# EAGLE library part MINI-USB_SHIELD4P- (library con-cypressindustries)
MINI USB 4 Pol. Source: www.cypressindustries.com

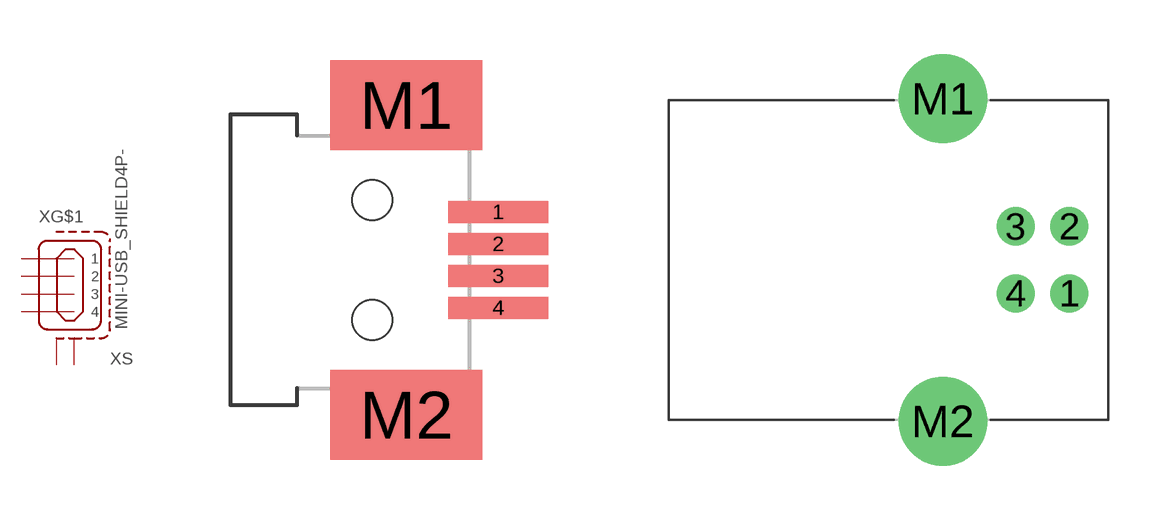
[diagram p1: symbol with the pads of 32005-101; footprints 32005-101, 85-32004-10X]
Designator prefix X; gates G$1=MINI-USB-4P- S=SHIELD_2

## MINI-USB_SHIELD4P-32005-101 (OC_FARNELL: unknown; OC_NEWARK: unknown)  [32005-101]
1  G$1:1  pas
2  G$1:2  pas
3  G$1:3  pas
4  G$1:4  pas
M1  S:S1  pas
M2  S:S2  pas

## MINI-USB_SHIELD4P-85-32004-10X (OC_FARNELL: unknown; OC_NEWARK: unknown)  [85-32004-10X]
Pads as for 32005-101

## MINI-USB_SHIELD4P-85-32004-30X-1 (OC_FARNELL: unknown; OC_NEWARK: unknown)  [85-32004-30X-1]
Pads as for 32005-101

## MINI-USB_SHIELD4P-85-32006-001-1 (OC_FARNELL: unknown; OC_NEWARK: unknown)  [85-32006-001-1]
Pads as for 32005-101

## MINI-USB_SHIELD4P-85-32006-201-1 (OC_FARNELL: unknown; OC_NEWARK: unknown)  [85-32006-201-1]
Pads as for 32005-101

## MINI-USB_SHIELD4P-85-32006-601-1 (OC_FARNELL: unknown; OC_NEWARK: unknown)  [85-32006-601-1]
Pads as for 32005-101

## MINI-USB_SHIELD4P-32005-00X (OC_FARNELL: unknown; OC_NEWARK: unknown)  [32005-00X]
Pads as for 32005-101

## MINI-USB_SHIELD4P-85-32004-00X (OC_FARNELL: unknown; OC_NEWARK: unknown)  [85-32004-00X]
Pads as for 32005-101

## Footprint 32005-101 (pad centres in mm)
MINI USB 4P R/A SMT Two Salient Point Source: http://www.cypressindustries.com/pdf/32005-101.pdf
smd 2.5 x 0.55: 1 3.15,1.2; 2 3.15,0.4; 3 3.15,-0.4; 4 3.15,-1.2
smd 3.8 x 2.25: M1 0.85,3.875; M2 0.85,-3.875
hole 1 at 0,1.5
hole 1 at 0,-1.5

## Footprint 85-32004-10X (pad centres in mm)
USB B TYPE SINGLE R/A DIP With Rear Shell, Without Rear Shell Source: http://www.cypressindustries.com/pdf/85-32004-10x.pdf
drill 0.92 pad 1.27 round: 1 4.71,-1.25; 2 4.71,1.25; 3 2.71,1.25; 4 2.71,-1.25
drill 2.3 pad 3 round: M1 0,6.02; M2 0,-6.02

## Footprint 85-32004-30X-1 (pad centres in mm)
USB B TYPE SINGLE VERTICAL DIP 3.6mm Data sheet ERROR for 2 Mounting holes 2.3mm Source: http://www.cypressindustries.com/pdf/85-32004-30x-1.pdf
drill 0.92 pad 1.27 round: 1 1.25,1.8; 2 -1.25,1.8; 3 -1.25,-1.8; 4 1.25,-1.8
drill 2.3 pad 3 round: M1 -6.02,-1.8; M2 6.02,-1.8

## Footprint 85-32006-001-1 (pad centres in mm)
1394-4P R/A DIP TWO Legs 2.0 Pitch IEEE1394 4 Pin Firewire Connector Source: http://www.cypressindustries.com/pdf/85-32006-001-1.pdf
drill 0.7 pad 1.016 round: 1 -1.6,4; 2 -0.8,6; 3 0,4; 4 0.8,6
drill 1 pad 1.4 long: M1 -4,0; M2 4,0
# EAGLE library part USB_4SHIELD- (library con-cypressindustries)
Quad USB Connector Source: www.cypressindustries.com

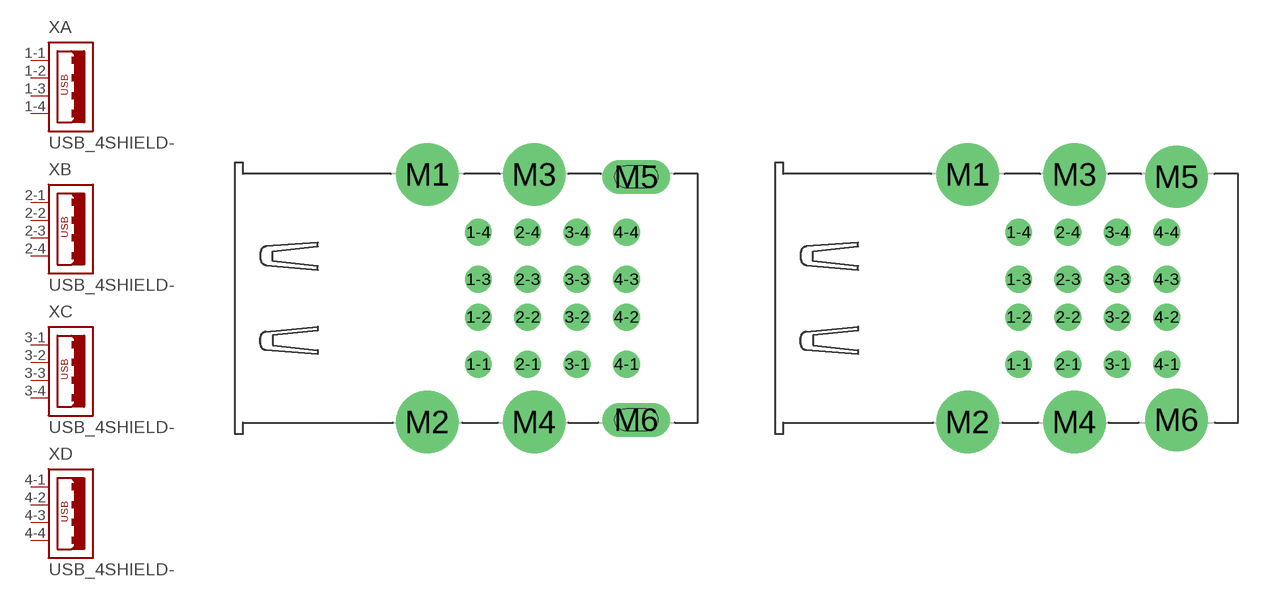
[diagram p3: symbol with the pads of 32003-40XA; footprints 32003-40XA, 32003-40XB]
Designator prefix X; gates A=USB4 B=USB4 C=USB4 D=USB4

## USB_4SHIELD-32003-40XA (OC_FARNELL: unknown; OC_NEWARK: unknown)  [32003-40XA]
1-1  A:1  pas
1-2  A:2  pas
1-3  A:3  pas
1-4  A:4  pas
2-1  B:1  pas
2-2  B:2  pas
2-3  B:3  pas
2-4  B:4  pas
3-1  C:1  pas
3-2  C:2  pas
3-3  C:3  pas
3-4  C:4  pas
4-1  D:1  pas
4-2  D:2  pas
4-3  D:3  pas
4-4  D:4  pas

## USB_4SHIELD-32003-40XB (OC_FARNELL: unknown; OC_NEWARK: unknown)  [32003-40XB]
Pads as for 32003-40XA

## Footprint 32003-40XA (pad centres in mm)
USB Quadruple A Type Flat - RA Dip Source: http://www.cypressindustries.com/pdf/ccusba-32003-40x.pdf
drill 0.92 pad 1.27 round: 1-1 2.71,-3.5; 1-2 2.71,-1; 1-3 2.71,1; 1-4 2.71,3.5; 2-1 5.33,-3.5; 2-2 5.33,-1; 2-3 5.33,1; 2-4 5.33,3.5; 3-1 7.95,-3.5; 3-2 7.95,-1; 3-3 7.95,1; 3-4 7.95,3.5; 4-1 10.57,-3.5; 4-2 10.57,-1; 4-3 10.57,1; 4-4 10.57,3.5
drill 2.3 pad 3 round: M1 0,6.57; M2 0,-6.57; M3 5.68,6.57; M4 5.68,-6.57
drill 1.2 pad 1.6 long: M5 11.1,6.45; M6 11.1,-6.45

## Footprint 32003-40XB (pad centres in mm)
USB Quadruple A Type Flat - RA Dip Source: http://www.cypressindustries.com/pdf/ccusba-32003-40x.pdf
drill 0.92 pad 1.27 round: 1-1 2.71,-3.5; 1-2 2.71,-1; 1-3 2.71,1; 1-4 2.71,3.5; 2-1 5.33,-3.5; 2-2 5.33,-1; 2-3 5.33,1; 2-4 5.33,3.5; 3-1 7.95,-3.5; 3-2 7.95,-1; 3-3 7.95,1; 3-4 7.95,3.5; 4-1 10.57,-3.5; 4-2 10.57,-1; 4-3 10.57,1; 4-4 10.57,3.5
drill 2.3 pad 3 round: M1 0,6.57; M2 0,-6.57; M3 5.68,6.57; M4 5.68,-6.57; M5 11.1,6.45; M6 11.1,-6.45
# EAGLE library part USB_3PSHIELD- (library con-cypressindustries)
Triple USB Connector Source: www.cypressindustries.com

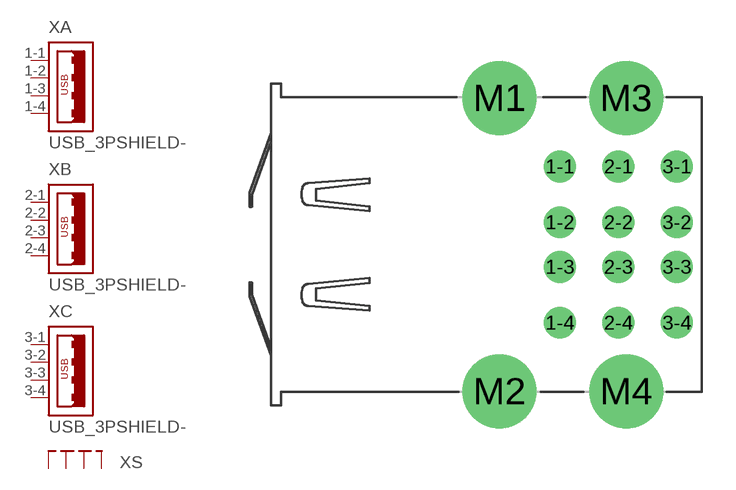
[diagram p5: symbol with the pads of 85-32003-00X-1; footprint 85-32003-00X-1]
Designator prefix X; gates A=USB4 B=USB4 C=USB4 S=SHIELD4

## USB_3PSHIELD-85-32003-00X-1 (OC_FARNELL: unknown; OC_NEWARK: unknown)  [85-32003-00X-1]
1-1  A:1  pas
1-2  A:2  pas
1-3  A:3  pas
1-4  A:4  pas
2-1  B:1  pas
2-2  B:2  pas
2-3  B:3  pas
2-4  B:4  pas
3-1  C:1  pas
3-2  C:2  pas
3-3  C:3  pas
3-4  C:4  pas
M1  S:S1  pas
M2  S:S2  pas
M3  S:S3  pas
M4  S:S4  pas

## Footprint 85-32003-00X-1 (pad centres in mm)
USB A TYPE TRIPLE R/A DIP Source: http://www.cypressindustries.com/pdf/85-32003-00x-1.pdf
drill 0.92 pad 1.27 round: 1-1 2.71,3.5; 1-2 2.71,1; 1-3 2.71,-1; 1-4 2.71,-3.5; 2-1 5.33,3.5; 2-2 5.33,1; 2-3 5.33,-1; 2-4 5.33,-3.5; 3-1 7.95,3.5; 3-2 7.95,1; 3-3 7.95,-1; 3-4 7.95,-3.5
drill 2.3 pad 3 round: M1 0,6.57; M2 0,-6.57; M3 5.68,6.57; M4 5.68,-6.57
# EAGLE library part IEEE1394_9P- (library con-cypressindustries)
IEEE 1394b Firewire Connector Bilingual / Beta Source: www.cypressindustries.com

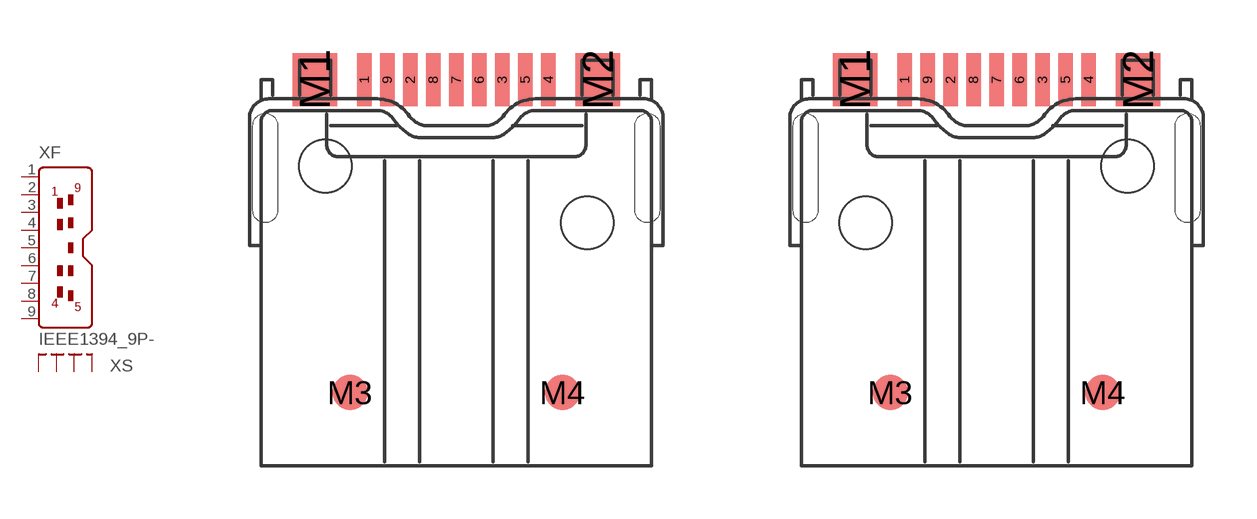
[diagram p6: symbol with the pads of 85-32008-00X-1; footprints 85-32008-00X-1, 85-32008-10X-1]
Designator prefix X; gates F=IEEE1394_9P S=SHIELD4

## IEEE1394_9P-85-32008-00X-1 (OC_FARNELL: unknown; OC_NEWARK: unknown)  [85-32008-00X-1]
1  F:1  pas
2  F:2  pas
3  F:3  pas
4  F:4  pas
5  F:5  pas
6  F:6  pas
7  F:7  pas
8  F:8  pas
9  F:9  pas
M1  S:S1  pas
M2  S:S2  pas
M3  S:S3  pas
M4  S:S4  pas

## IEEE1394_9P-85-32008-10X-1 (OC_FARNELL: unknown; OC_NEWARK: unknown)  [85-32008-10X-1]
Pads as for 85-32008-00X-1

## Footprint 85-32008-00X-1 (pad centres in mm)
1394-9P R/A SMT Bilingual IEEE1394 9 Pin Firewire Connector Source: http://www.cypressindustries.com/pdf/85-32008-00x-1.pdf
smd 0.4 x 1.5: 1 -2.6,10.05; 2 -1.3,10.05; 3 1.3,10.05; 4 2.6,10.05; 5 1.95,10.05; 6 0.65,10.05; 7 0,10.05; 8 -0.65,10.05; 9 -1.95,10.05
smd 1.25 x 1.5: M1 -4,10.05; M2 4,10.05
smd 1 x 1: M3 -3,1.2; M4 3,1.2
hole 1.5 at 3.7,6
hole 1.5 at -3.7,7.6

## Footprint 85-32008-10X-1 (pad centres in mm)
1394b-9P R/A SMT Beta IEEE1394 9 Pin Firewire Connector Source: http://www.cypressindustries.com/pdf/85-32008-10x-1.pdf
smd 0.4 x 1.5: 1 -2.6,10.05; 2 -1.3,10.05; 3 1.3,10.05; 4 2.6,10.05; 5 1.95,10.05; 6 0.65,10.05; 7 0,10.05; 8 -0.65,10.05; 9 -1.95,10.05
smd 1.25 x 1.5: M1 -4,10.05; M2 4,10.05
smd 1 x 1: M3 -3,1.2; M4 3,1.2
hole 1.5 at -3.7,6
hole 1.5 at 3.7,7.6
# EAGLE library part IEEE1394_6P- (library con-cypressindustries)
IEEE1394 6P Firewire Receptacle Source: www.cypressindustries.com

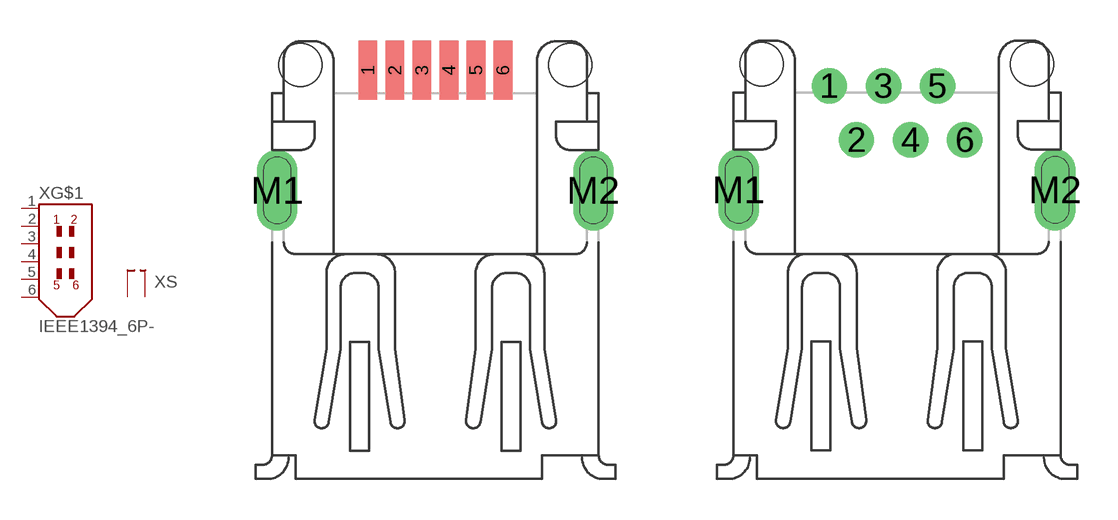
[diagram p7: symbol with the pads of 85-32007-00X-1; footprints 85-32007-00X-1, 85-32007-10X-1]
Designator prefix X; gates G$1=IEEE1394_6P S=SHIELD2

## IEEE1394_6P-85-32007-00X-1 (OC_FARNELL: unknown; OC_NEWARK: unknown)  [85-32007-00X-1]
1  G$1:1  pas
2  G$1:2  pas
3  G$1:3  pas
4  G$1:4  pas
5  G$1:5  pas
6  G$1:6  pas
M1  S:S1  pas
M2  S:S2  pas

## IEEE1394_6P-85-32007-10X-1 (OC_FARNELL: unknown; OC_NEWARK: unknown)  [85-32007-10X-1]
Pads as for 85-32007-00X-1

## IEEE1394_6P-85-32007-20X-1 (OC_FARNELL: unknown; OC_NEWARK: unknown)  [85-32007-20X-1]
Pads as for 85-32007-00X-1

## IEEE1394_6P-85-32007-50X-1 (OC_FARNELL: unknown; OC_NEWARK: unknown)  [85-32007-50X-1]
Pads as for 85-32007-00X-1

## IEEE1394_6P-85-32007-60X-1 (OC_FARNELL: unknown; OC_NEWARK: unknown)  [85-32007-60X-1]
Pads as for 85-32007-00X-1

## Footprint 85-32007-00X-1 (pad centres in mm)
1394-6P R/A SMT IEEE1394 6 Pin Firewire Connector Source: http://www.cypressindustries.com/pdf/85-32007-00x-1.pdf
smd 0.7 x 2.2: 1 -2.5,4.45; 2 -1.5,4.45; 3 -0.5,4.45; 4 0.5,4.45; 5 1.5,4.45; 6 2.5,4.45
drill 1 pad 1.422 long: M1 -5.85,0; M2 5.85,0
hole 1.6 at -5,4.65
hole 1.6 at 5,4.65

## Footprint 85-32007-10X-1 (pad centres in mm)
1394-6P R/A DIP IEEE1394 6 Pin Firewire Connector Source: http://www.cypressindustries.com/pdf/85-32007-10x-1.pdf
drill 0.8 pad 1.27 round: 1 -2.5,3.85; 2 -1.5,1.85; 3 -0.5,3.85; 4 0.5,1.85; 5 1.5,3.85; 6 2.5,1.85
drill 1 pad 1.422 long: M1 -5.85,0; M2 5.85,0
hole 1.6 at -5,4.65
hole 1.6 at 5,4.65

## Footprint 85-32007-20X-1 (pad centres in mm)
1394-6P VERTICAL DIP IEEE1394 6 Pin Firewire Connector Source: http://www.cypressindustries.com/pdf/85-32007-20x-1.pdf
drill 0.8 pad 1.27 round: 1 2.5,1.25; 2 1.5,-1.25; 3 0.5,1.25; 4 -0.5,-1.25; 5 -1.5,1.25; 6 -2.5,-1.25
drill 1 pad 1.27 long: M1 -5.85,0; M2 5.85,0; M3 0,3.3

## Footprint 85-32007-50X-1 (pad centres in mm)
1394-6P UP-RIGHT IEEE1394 6 Pin Firewire Connector Source: http://www.cypressindustries.com/pdf/85-32007-50x-1.pdf
drill 0.8 pad 1.27 round: 1 7.8,1.5; 2 7.8,-1.5; 3 5.8,1.5; 4 5.8,-1.5; 5 3.8,1.5; 6 3.8,-1.5
drill 1 pad 1.422 long: M1 9.8,0; M2 3.25,3.6; M3 3.25,-3.6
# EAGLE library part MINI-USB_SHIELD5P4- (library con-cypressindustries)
MINI USB-B R/A W/O POST 5 pol. Source: www.cypressindustries.com

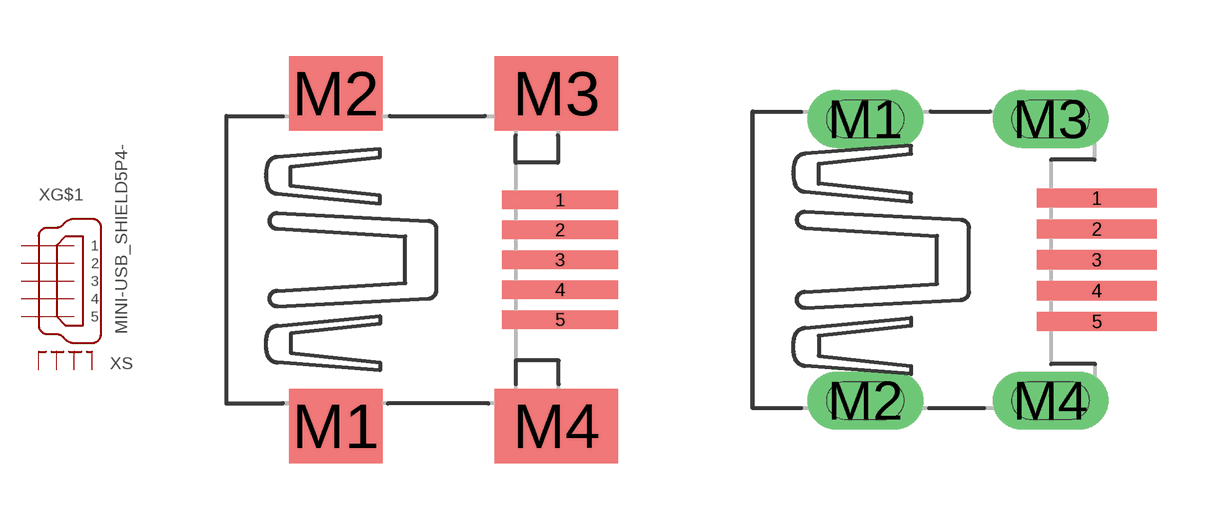
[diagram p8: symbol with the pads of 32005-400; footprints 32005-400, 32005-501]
Designator prefix X; gates G$1=MINI-USB-5 S=SHIELD4

## MINI-USB_SHIELD5P4-32005-400 (OC_FARNELL: unknown; OC_NEWARK: unknown)  [32005-400]
1  G$1:1  pas
2  G$1:2  pas
3  G$1:3  pas
4  G$1:4  pas
5  G$1:5  pas
M1  S:S1  pas
M2  S:S2  pas
M3  S:S3  pas
M4  S:S4  pas

## MINI-USB_SHIELD5P4-32005-501 (OC_FARNELL: unknown; OC_NEWARK: unknown)  [32005-501]
Pads as for 32005-400

## Footprint 32005-400 (pad centres in mm)
MINI USB-B R/A SMT W/O POST Source: http://www.cypressindustries.com/pdf/32005-400.pdf
smd 3.1 x 0.5: 1 3,1.6; 2 3,0.8; 3 3,0; 4 3,-0.8; 5 3,-1.6
smd 2.5 x 2: M1 -3,-4.45; M2 -3,4.45
smd 3.3 x 2: M3 2.9,4.45; M4 2.9,-4.45

## Footprint 32005-501 (pad centres in mm)
MINI USB_B/F/SMT/TYPE III Source: http://www.cypressindustries.com/pdf/ccmusb-32005-501.pdf
smd 3.1 x 0.5: 1 3,1.6; 2 3,0.8; 3 3,0; 4 3,-0.8; 5 3,-1.6
drill 1 pad 1.422 long: M1 -3,3.65; M2 -3,-3.65; M3 1.8,3.65; M4 1.8,-3.65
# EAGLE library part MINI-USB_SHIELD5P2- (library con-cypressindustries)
MINI USB-B R/A DIP 5pol. Source: www.cypressindustries.com

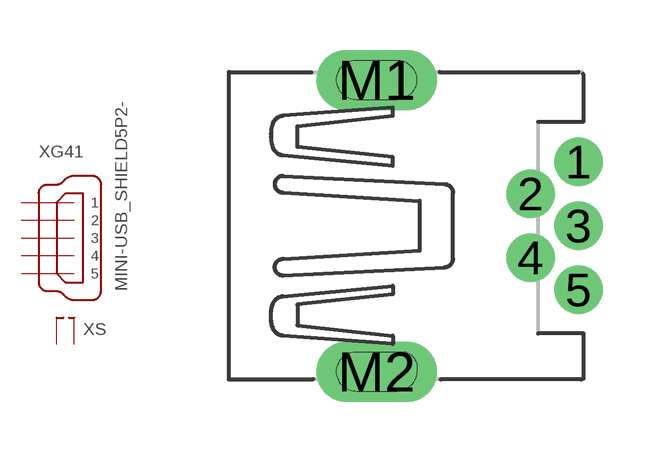
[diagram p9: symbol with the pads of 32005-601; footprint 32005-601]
Designator prefix X; gates G41=MINI-USB-5 S=SHIELD2

## MINI-USB_SHIELD5P2-32005-601 (OC_FARNELL: unknown; OC_NEWARK: unknown)  [32005-601]
1  G41:1  pas
2  G41:2  pas
3  G41:3  pas
4  G41:4  pas
5  G41:5  pas
M1  S:S1  pas
M2  S:S2  pas

## Footprint 32005-601 (pad centres in mm)
MINI USB-B R/A DIP Source: http://www.cypressindustries.com/pdf/32005-601.pdf
drill 0.7 pad 1.016 round: 1 2.825,1.6; 2 1.625,0.8; 3 2.825,0; 4 1.625,-0.8; 5 2.825,-1.6
drill 1 pad 1.422 long: M1 -2.225,3.65; M2 -2.225,-3.65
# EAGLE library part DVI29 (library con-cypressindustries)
DVI 29 Connctor Source: http://www.cypressindustries.com/pdf/CCDVI-29DVISIR-A-2.pdf

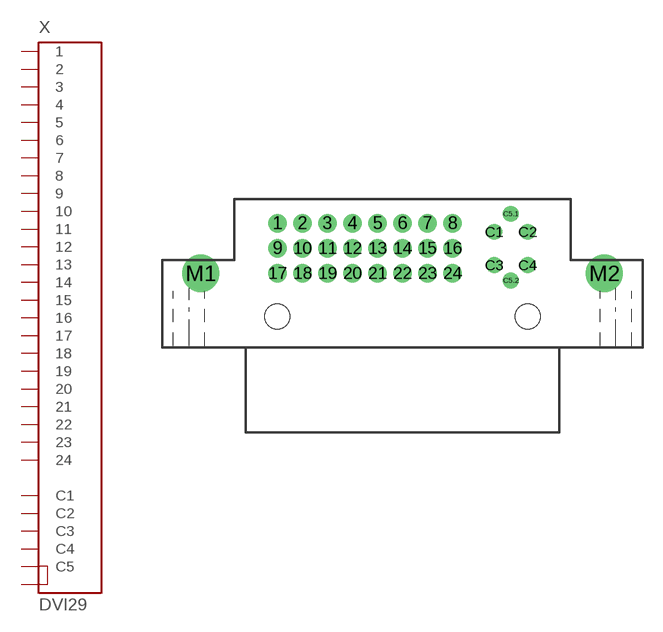
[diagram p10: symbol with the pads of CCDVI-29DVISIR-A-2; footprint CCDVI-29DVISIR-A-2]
Designator prefix X

## DVI29 (OC_FARNELL: unknown; OC_NEWARK: unknown)  [CCDVI-29DVISIR-A-2]
1  1  pas
2  2  pas
3  3  pas
4  4  pas
5  5  pas
6  6  pas
7  7  pas
8  8  pas
9  9  pas
10  10  pas
11  11  pas
12  12  pas
13  13  pas
14  14  pas
15  15  pas
16  16  pas
17  17  pas
18  18  pas
19  19  pas
20  20  pas
21  21  pas
22  22  pas
23  23  pas
24  24  pas
C1  C1  pas
C2  C2  pas
C3  C3  pas
C4  C4  pas
C5.1  C5  pas
C5.2  C5.2  pas

## Footprint CCDVI-29DVISIR-A-2 (pad centres in mm)
FEMALE DVI CONNECTOR INTEGRATED 29 - RIGHT ANGLE Source: http://www.cypressindustries.com/pdf/CCDVI-29DVISIR-A-2.pdf
drill 0.9 pad 1.27 round: 1 -9.525,9.04; 2 -7.62,9.04; 3 -5.715,9.04; 4 -3.81,9.04; 5 -1.905,9.04; 6 0,9.04; 7 1.905,9.04; 8 3.81,9.04; 9 -9.525,7.135; 10 -7.62,7.135; 11 -5.715,7.135; 12 -3.81,7.135; 13 -1.905,7.135; 14 0,7.135; 15 1.905,7.135; 16 3.81,7.135; 17 -9.525,5.23; 18 -7.62,5.23; 19 -5.715,5.23; 20 -3.81,5.23; 21 -1.905,5.23; 22 0,5.23; 23 1.905,5.23; 24 3.81,5.23
drill 0.7 pad 1.016 round: C1 6.985,8.382; C2 9.525,8.382; C3 6.985,5.842; C4 9.525,5.842; C5.1 8.255,9.745; C5.2 8.255,4.665
drill 1.9 pad 2.54 round: M1 -15.365,5.205; M2 15.365,5.205
hole 1.9 at -9.525,1.93
hole 1.9 at 9.525,1.93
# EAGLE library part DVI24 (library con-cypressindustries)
DIGITAL DVI 24 Connctor Source: http://www.cypressindustries.com/pdf/CCDVI-24DVISD-DA3.pdf

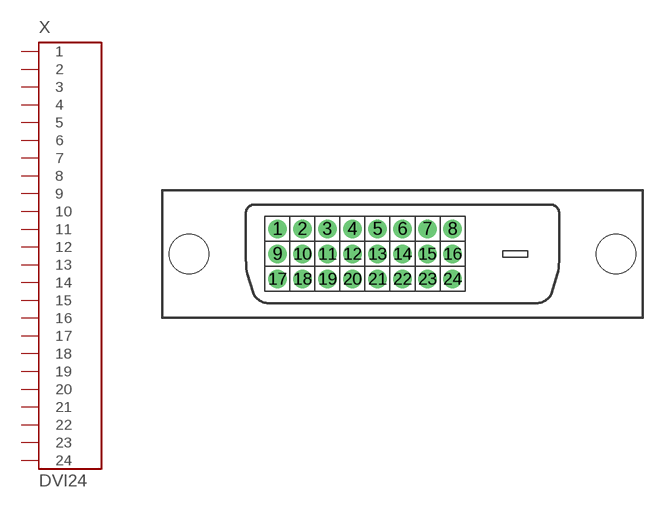
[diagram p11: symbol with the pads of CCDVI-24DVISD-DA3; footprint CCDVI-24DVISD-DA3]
Designator prefix X

## DVI24 (MPN: DVI2425X; OC_FARNELL: unknown; OC_NEWARK: 95K3853)  [CCDVI-24DVISD-DA3]
1  1  pas
2  2  pas
3  3  pas
4  4  pas
5  5  pas
6  6  pas
7  7  pas
8  8  pas
9  9  pas
10  10  pas
11  11  pas
12  12  pas
13  13  pas
14  14  pas
15  15  pas
16  16  pas
17  17  pas
18  18  pas
19  19  pas
20  20  pas
21  21  pas
22  22  pas
23  23  pas
24  24  pas

## Footprint CCDVI-24DVISD-DA3 (pad centres in mm)
FEMALE DVI CONNECTOR DIGITAL 24DVISDX-X-X Source: http://www.cypressindustries.com/pdf/CCDVI-24DVISD-DA3.pdf
drill 0.9 pad 1.4 round: 1 -9.53,1.905; 2 -7.625,1.905; 3 -5.72,1.905; 4 -3.815,1.905; 5 -1.91,1.905; 6 -0.005,1.905; 7 1.9,1.905; 8 3.805,1.905; 9 -9.53,0; 10 -7.625,0; 11 -5.72,0; 12 -3.815,0; 13 -1.91,0; 14 -0.005,0; 15 1.9,0; 16 3.805,0; 17 -9.53,-1.905; 18 -7.625,-1.905; 19 -5.72,-1.905; 20 -3.815,-1.905; 21 -1.91,-1.905; 22 -0.005,-1.905; 23 1.9,-1.905; 24 3.805,-1.905
hole 3 at -16.26,0
hole 3 at 16.26,0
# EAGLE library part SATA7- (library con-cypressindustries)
Serial ATA 7 Pol. Source: www.cypressindustries.com

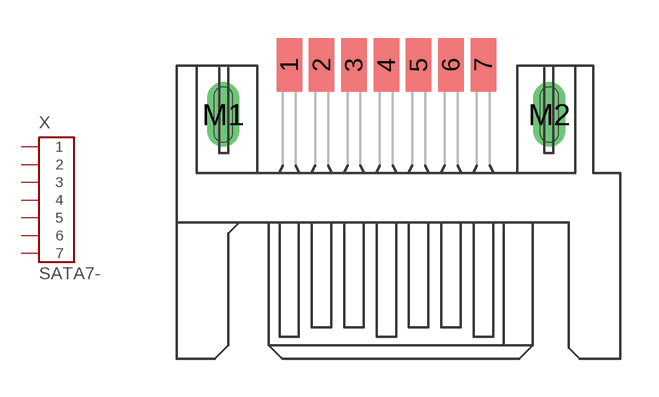
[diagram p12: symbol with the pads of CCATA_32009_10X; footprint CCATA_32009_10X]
Designator prefix X

## SATA7-32009-10X (OC_FARNELL: unknown; OC_NEWARK: unknown)  [CCATA_32009_10X]
1  1  pas
2  2  pas
3  3  pas
4  4  pas
5  5  pas
6  6  pas
7  7  pas

## Footprint CCATA_32009_10X (pad centres in mm)
SERIAL ATA 7P R/A SMT Source: http://www.cypressindustries.com/pdf/ccata_32009_10x.pdf
smd 1 x 2.1: 1 -3.81,11.2; 2 -2.54,11.2; 3 -1.27,11.2; 4 0,11.2; 5 1.27,11.2; 6 2.54,11.2; 7 3.81,11.2
drill 0.7 pad 1.27 long: M1 -6.4,9.25; M2 6.4,9.25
